VERSION 5.8 ;
BUSBITCHARS "[]" ;
DIVIDERCHAR "/" ;
UNITS
  DATABASE MICRONS 1000 ;
END UNITS
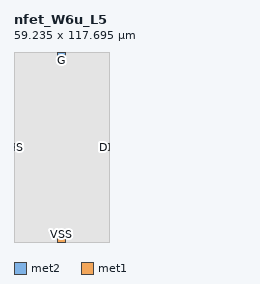
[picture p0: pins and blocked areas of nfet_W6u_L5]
MACRO nfet_W6u_L5
  CLASS BLOCK ;
  ORIGIN 0 0 ;
  FOREIGN nfet_W6u_L5 0 0 ;
  SIZE 59.235 BY 117.695 ;
  SYMMETRY X Y ;
  PIN D
    DIRECTION INOUT ;
    USE SIGNAL ;
    PORT
      LAYER met2 ;
        RECT 56.865 56.48 59.235 61.215 ;
    END
  END D
  PIN G
    DIRECTION INPUT ;
    USE SIGNAL ;
    PORT
      LAYER met2 ;
        RECT 27.25 115.325 31.985 117.695 ;
    END
  END G
  PIN S
    DIRECTION INOUT ;
    USE SIGNAL ;
    PORT
      LAYER met2 ;
        RECT 0 56.48 2.37 61.215 ;
    END
  END S
  PIN VSS
    DIRECTION INOUT ;
    USE GROUND ;
    PORT
      LAYER met1 ;
        RECT 27.25 0 31.985 2.37 ;
    END
  END VSS
  OBS
    LAYER met1 ;
      RECT 0 0 59.235 117.695 ;
  END
END nfet_W6u_L5
END LIBRARY
